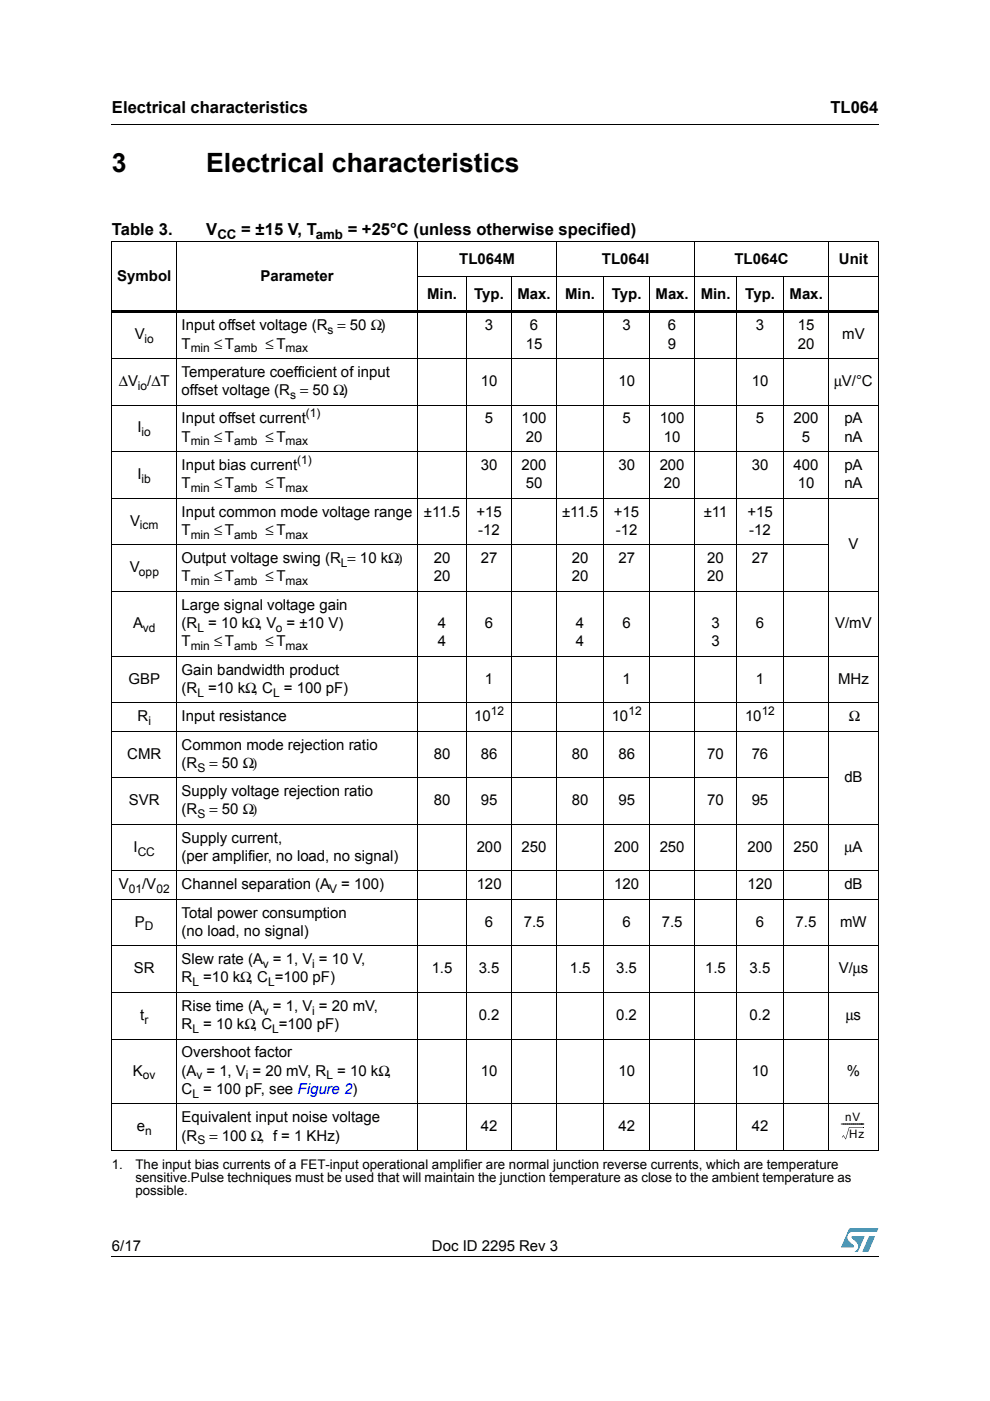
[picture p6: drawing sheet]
<svg xmlns="http://www.w3.org/2000/svg" width="210mm" height="297mm" viewBox="0 0 210 297" stroke-linecap="round" stroke-linejoin="round" font-family="sans-serif">
<defs><g id="words">
<g font-size="5.6">
<text x="23.7" y="36.4">3</text>
<text x="43.7" y="36.4">Electrical characteristics</text>
</g>
<g font-size="3.5">
<text x="23.7" y="23.9">Electrical characteristics</text>
<text x="176.1" y="23.9">TL064</text>
<text x="23.7" y="49.8">Table 3.</text>
<text x="43.7" y="49.8">V</text>
<text x="51.2" y="49.8">= ±15 V, T</text>
<text x="73.7" y="49.8">= +25°C (unless otherwise specified)</text>
</g>
<g font-size="3.2">
<text x="24.9" y="59.6">Symbol</text>
<text x="55.2" y="59.6">Parameter</text>
<text x="97.4" y="55.9">TL064M</text>
<text x="127.6" y="55.9">TL064I</text>
<text x="155.7" y="55.9">TL064C</text>
<text x="177.9" y="55.9">Unit</text>
<text x="90.6" y="63.3">Min.</text>
<text x="100.6" y="63.3">Typ.</text>
<text x="109.7" y="63.3">Max.</text>
<text x="119.8" y="63.3">Min.</text>
<text x="129.7" y="63.3">Typ.</text>
<text x="139" y="63.3">Max.</text>
<text x="148.6" y="63.3">Min.</text>
<text x="158" y="63.3">Typ.</text>
<text x="167.4" y="63.3">Max.</text>
<text x="28.6" y="71.9">V</text>
<text x="38.5" y="70">Input offset voltage (R = 50 Ω)</text>
<text x="102.8" y="70">3</text>
<text x="112.4" y="70">6</text>
<text x="132" y="70">3</text>
<text x="141.6" y="70">6</text>
<text x="160.3" y="70">3</text>
<text x="169.1" y="70">15</text>
<text x="178.6" y="71.9">mV</text>
<text x="38.5" y="73.9">T</text>
<text x="45.4" y="73.9">≤ T</text>
<text x="56.3" y="73.9">≤ T</text>
<text x="111.5" y="73.9">15</text>
<text x="141.6" y="73.9">9</text>
<text x="169.1" y="73.9">20</text>
<text x="25.2" y="81.8">ΔV /ΔT</text>
<text x="38.5" y="79.9">Temperature coefficient of input</text>
<text x="38.5" y="83.8">offset voltage (R = 50 Ω)</text>
<text x="101.9" y="81.8">10</text>
<text x="131.1" y="81.8">10</text>
<text x="159.4" y="81.8">10</text>
<text x="176.8" y="81.8">μV/°C</text>
<text x="38.5" y="89.8">Input offset current</text>
<text x="102.8" y="89.8">5</text>
<text x="110.6" y="89.8">100</text>
<text x="132" y="89.8">5</text>
<text x="139.9" y="89.8">100</text>
<text x="160.3" y="89.8">5</text>
<text x="168.3" y="89.8">200</text>
<text x="179" y="89.8">pA</text>
<text x="29.2" y="91.7">I</text>
<text x="38.5" y="93.6">T</text>
<text x="45.4" y="93.6">≤ T</text>
<text x="56.3" y="93.6">≤ T</text>
<text x="111.5" y="93.6">20</text>
<text x="140.8" y="93.6">10</text>
<text x="170" y="93.6">5</text>
<text x="179" y="93.6">nA</text>
<text x="29.2" y="101.6">I</text>
<text x="38.5" y="99.6">Input bias current</text>
<text x="101.9" y="99.6">30</text>
<text x="110.6" y="99.6">200</text>
<text x="131.1" y="99.6">30</text>
<text x="139.9" y="99.6">200</text>
<text x="159.4" y="99.6">30</text>
<text x="168.3" y="99.6">400</text>
<text x="179" y="99.6">pA</text>
<text x="38.5" y="103.5">T</text>
<text x="45.4" y="103.5">≤ T</text>
<text x="56.3" y="103.5">≤ T</text>
<text x="111.5" y="103.5">50</text>
<text x="140.8" y="103.5">20</text>
<text x="169.1" y="103.5">10</text>
<text x="179" y="103.5">nA</text>
<text x="27.6" y="111.5">V</text>
<text x="38.5" y="109.5">Input common mode voltage range</text>
<text x="38.5" y="113.4">T</text>
<text x="45.4" y="113.4">≤ T</text>
<text x="56.3" y="113.4">≤ T</text>
<text x="89.9" y="109.5">±11.5</text>
<text x="101" y="109.5">+15</text>
<text x="101.4" y="113.4">-12</text>
<text x="119.2" y="109.5">±11.5</text>
<text x="130.2" y="109.5">+15</text>
<text x="130.6" y="113.4">-12</text>
<text x="149.2" y="109.5">±11</text>
<text x="158.5" y="109.5">+15</text>
<text x="158.9" y="113.4">-12</text>
<text x="38.5" y="119.4">Output voltage swing (R = 10 kΩ)</text>
<text x="92" y="119.4">20</text>
<text x="101.9" y="119.4">27</text>
<text x="121.2" y="119.4">20</text>
<text x="131.1" y="119.4">27</text>
<text x="150" y="119.4">20</text>
<text x="159.4" y="119.4">27</text>
<text x="179.9" y="116.4">V</text>
<text x="27.5" y="121.3">V</text>
<text x="38.5" y="123.3">T</text>
<text x="45.4" y="123.3">≤ T</text>
<text x="56.3" y="123.3">≤ T</text>
<text x="92" y="123.3">20</text>
<text x="121.2" y="123.3">20</text>
<text x="150" y="123.3">20</text>
<text x="38.5" y="129.3">Large signal voltage gain</text>
<text x="28.2" y="133.2">A</text>
<text x="38.5" y="137">T</text>
<text x="38.5" y="133.2">(R</text>
<text x="44.2" y="133.2">= 10 kΩ, V = ±10 V)</text>
<text x="45.4" y="137">≤ T</text>
<text x="56.3" y="137">≤ T</text>
<text x="92.8" y="133.2">4</text>
<text x="92.8" y="137">4</text>
<text x="102.8" y="133.2">6</text>
<text x="122.1" y="133.2">4</text>
<text x="122.1" y="137">4</text>
<text x="132" y="133.2">6</text>
<text x="150.8" y="133.2">3</text>
<text x="150.8" y="137">3</text>
<text x="160.3" y="133.2">6</text>
<text x="177.1" y="133.2">V/mV</text>
<text x="38.5" y="143">Gain bandwidth product</text>
<text x="27.2" y="145">GBP</text>
<text x="38.5" y="146.9">(R</text>
<text x="44.2" y="146.9">=10 kΩ, C</text>
<text x="60.2" y="146.9">= 100 pF)</text>
<text x="102.8" y="145">1</text>
<text x="132" y="145">1</text>
<text x="160.3" y="145">1</text>
<text x="177.7" y="145">MHz</text>
<text x="29.2" y="152.9">R</text>
<text x="38.5" y="152.9">Input resistance</text>
<text x="100.5" y="152.9">10</text>
<text x="129.7" y="152.9">10</text>
<text x="158" y="152.9">10</text>
<text x="179.9" y="152.9">Ω</text>
<text x="27" y="160.8">CMR</text>
<text x="38.5" y="158.9">Common mode rejection ratio</text>
<text x="92" y="160.8">80</text>
<text x="101.9" y="160.8">86</text>
<text x="121.2" y="160.8">80</text>
<text x="131.1" y="160.8">86</text>
<text x="150" y="160.8">70</text>
<text x="159.4" y="160.8">76</text>
<text x="38.5" y="162.8">(R</text>
<text x="44.4" y="162.8">= 50 Ω)</text>
<text x="179" y="165.8">dB</text>
<text x="27.3" y="170.7">SVR</text>
<text x="38.5" y="168.8">Supply voltage rejection ratio</text>
<text x="38.5" y="172.7">(R</text>
<text x="44.4" y="172.7">= 50 Ω)</text>
<text x="92" y="170.7">80</text>
<text x="101.9" y="170.7">95</text>
<text x="121.2" y="170.7">80</text>
<text x="131.1" y="170.7">95</text>
<text x="150" y="170.7">70</text>
<text x="159.4" y="170.7">95</text>
<text x="38.5" y="178.7">Supply current,</text>
<text x="28.3" y="180.6">I</text>
<text x="38.5" y="182.5">(per amplifier, no load, no signal)</text>
<text x="101.1" y="180.6">200</text>
<text x="110.6" y="180.6">250</text>
<text x="130.2" y="180.6">200</text>
<text x="139.9" y="180.6">250</text>
<text x="158.5" y="180.6">200</text>
<text x="168.2" y="180.6">250</text>
<text x="179.1" y="180.6">μA</text>
<text x="25.2" y="188.6">V</text>
<text x="30.1" y="188.6">/V</text>
<text x="38.5" y="188.6">Channel separation (A</text>
<text x="72.4" y="188.6">= 100)</text>
<text x="101.1" y="188.6">120</text>
<text x="130.2" y="188.6">120</text>
<text x="158.5" y="188.6">120</text>
<text x="179" y="188.6">dB</text>
<text x="28.6" y="196.5">P</text>
<text x="38.5" y="194.5">Total power consumption</text>
<text x="102.8" y="196.5">6</text>
<text x="111" y="196.5">7.5</text>
<text x="132" y="196.5">6</text>
<text x="140.3" y="196.5">7.5</text>
<text x="160.3" y="196.5">6</text>
<text x="168.7" y="196.5">7.5</text>
<text x="178.1" y="196.5">mW</text>
<text x="38.5" y="198.4">(no load, no signal)</text>
<text x="28.4" y="206.4">SR</text>
<text x="38.5" y="208.3">R</text>
<text x="38.5" y="204.4">Slew rate (A = 1, V = 10 V,</text>
<text x="43.1" y="208.3">=10 kΩ, C =100 pF)</text>
<text x="91.5" y="206.4">1.5</text>
<text x="101.5" y="206.4">3.5</text>
<text x="120.8" y="206.4">1.5</text>
<text x="130.7" y="206.4">3.5</text>
<text x="149.5" y="206.4">1.5</text>
<text x="158.9" y="206.4">3.5</text>
<text x="177.8" y="206.4">V/μs</text>
<text x="38.5" y="214.3">Rise time (A = 1, V = 20 mV,</text>
<text x="29.7" y="216.2">t</text>
<text x="38.5" y="218.2">R</text>
<text x="43.1" y="218.2">= 10 kΩ, C =100 pF)</text>
<text x="101.5" y="216.2">0.2</text>
<text x="130.7" y="216.2">0.2</text>
<text x="158.9" y="216.2">0.2</text>
<text x="179.3" y="216.2">μs</text>
<text x="38.5" y="224.2">Overshoot factor</text>
<text x="28.2" y="228">K</text>
<text x="38.5" y="228">(A = 1, V = 20 mV, R</text>
<text x="38.5" y="231.9">C</text>
<text x="43.1" y="231.9">= 100 pF, see Figure 2)</text>
<text x="71.5" y="228">= 10 kΩ,</text>
<text x="101.9" y="228">10</text>
<text x="131.1" y="228">10</text>
<text x="159.4" y="228">10</text>
<text x="179.6" y="228">%</text>
<text x="29" y="239.9">e</text>
<text x="38.5" y="237.9">Equivalent input noise voltage</text>
<text x="101.9" y="239.9">42</text>
<text x="131.1" y="239.9">42</text>
<text x="159.4" y="239.9">42</text>
<text x="38.5" y="241.8">(R</text>
<text x="44.4" y="241.8">= 100 Ω, f = 1 KHz)</text>
<text x="23.7" y="265.1">6/17</text>
<text x="91.6" y="265.1">Doc ID 2295 Rev 3</text>
</g>
<g font-size="2.8">
<text x="46.1" y="50.7">CC</text>
<text x="67" y="50.7">amb</text>
<text x="23.7" y="247.8">1.</text>
<text x="28.7" y="247.8">The input bias currents of a FET-input operational amplifier are normal junction reverse currents, which are temperature</text>
<text x="28.7" y="250.6">sensitive.Pulse techniques must be used that will maintain the junction temperature as close to the ambient temperature as</text>
<text x="28.7" y="253.4">possible.</text>
</g>
<g font-size="2.5">
<text x="69.4" y="70.8">s</text>
<text x="30.6" y="72.7">io</text>
<text x="40.4" y="74.7">min</text>
<text x="49.6" y="74.7">amb</text>
<text x="60.6" y="74.7">max</text>
<text x="29.2" y="82.6">io</text>
<text x="61.5" y="84.6">s</text>
<text x="64.9" y="88.5">(1)</text>
<text x="30" y="92.5">io</text>
<text x="40.4" y="94.4">min</text>
<text x="49.6" y="94.4">amb</text>
<text x="60.6" y="94.4">max</text>
<text x="63" y="98.4">(1)</text>
<text x="30" y="102.4">ib</text>
<text x="40.4" y="104.3">min</text>
<text x="49.6" y="104.3">amb</text>
<text x="60.6" y="104.3">max</text>
<text x="29.7" y="112.2">icm</text>
<text x="40.4" y="114.2">min</text>
<text x="49.6" y="114.2">amb</text>
<text x="60.6" y="114.2">max</text>
<text x="29.5" y="122.1">opp</text>
<text x="40.4" y="124.1">min</text>
<text x="49.6" y="124.1">amb</text>
<text x="60.6" y="124.1">max</text>
<text x="72.3" y="120.2">L</text>
<text x="30.3" y="133.9">vd</text>
<text x="40.4" y="137.8">min</text>
<text x="41.8" y="133.9">L</text>
<text x="49.6" y="137.8">amb</text>
<text x="58.5" y="133.9">o</text>
<text x="60.6" y="137.8">max</text>
<text x="41.8" y="147.7">L</text>
<text x="57.9" y="147.7">L</text>
<text x="31.5" y="153.7">i</text>
<text x="104.1" y="151.6">12</text>
<text x="133.2" y="151.6">12</text>
<text x="161.5" y="151.6">12</text>
<text x="41.8" y="163.6">S</text>
<text x="41.8" y="173.5">S</text>
<text x="29.2" y="181.4">CC</text>
<text x="27.3" y="189.3">01</text>
<text x="33.1" y="189.3">02</text>
<text x="69.8" y="189.3">V</text>
<text x="30.7" y="197.3">D</text>
<text x="40.8" y="209.1">L</text>
<text x="55.7" y="205.2">v</text>
<text x="56.9" y="209.1">L</text>
<text x="66.2" y="205.2">i</text>
<text x="55.7" y="215.1">v</text>
<text x="66.2" y="215.1">i</text>
<text x="30.6" y="217">r</text>
<text x="40.8" y="219">L</text>
<text x="57.7" y="219">L</text>
<text x="30.3" y="228.9">ov</text>
<text x="40.8" y="232.7">L</text>
<text x="41.6" y="228.9">v</text>
<text x="52.1" y="228.9">i</text>
<text x="69.2" y="228.9">L</text>
<text x="178.3" y="238.9">-----------</text>
<text x="179.2" y="237.6">nV</text>
<text x="30.8" y="240.7">n</text>
<text x="41.8" y="242.6">S</text>
<text x="180" y="241.2">Hz</text>
</g>
</g></defs>
<g fill="#0099d8">
<path d="M184.3 262.1h1.2l-1.4 3.3h-1.3z"/>
<path d="M180.1 260.5h6.1l-.3 .7h-5.1a1.13 1.13 0 0 0-1.1 .7 1.13 1.13 0 0 0 .3 1.2l1 1v.3l-2.7 .1z"/>
<path d="M180.6 262.1h2.7l-1.4 3.3h-.7a1.18 1.18 0 0 0 .5-1.9l-1.1-1.1z"/>
</g>
<path d="M23.6 26.2l.1 .2zM23.6 65.9h162.7v.5h-162.7zM180 239h.1l-.7 2.5h-.1zM183 239v.1zM178.5 241.1l.1 .1zM178.8 240.7l-.2 .5zM179.3 241.5h.1zM178.8 240.7l.5 .8zM23.6 266.3l.1 .1z" fill="#000"/>
<g fill="none" stroke="#000" stroke-width=".21">
<path d="M23.7 26.3h162.6M23.6 51.3h162.7M23.7 51.4v24.5M37.4 51.2v24.9M88.4 58.7h97.9M88.5 51.2v192.8M98.9 58.6v185.4M108.5 58.6v185.4M118 51.2v192.8M128 58.6v185.4M137.8 58.6v185.4M147.3 51.2v192.8"/>
<path d="M156.2 58.6v185.4M166.1 58.6v185.4M175.7 51.2v192.8M186.2 51.4v192.4M23.7 76.1v9.7M37.5 75.9v10.1M186.3 76h-162.7M23.6 85.9h162.7M23.6 95.8h162.7M23.7 86v157.8M37.4 85.8v158.2M23.6 105.6h162.7"/>
<path d="M23.6 115.5h152.2M23.6 125.4h162.7M23.6 139.1h162.7M23.6 149h162.7M23.6 155h162.7M23.6 164.9h152.2M23.6 174.8h162.7M23.6 184.7h162.7M23.6 190.7h162.7M23.6 200.5h162.7M23.6 210.4h162.7M23.6 220.3h162.7"/>
<path d="M23.6 234.1h162.7M180 239h3M23.6 243.9h162.7M23.7 266.3h162.6"/>
</g>
<use href="#words"/>
</svg>
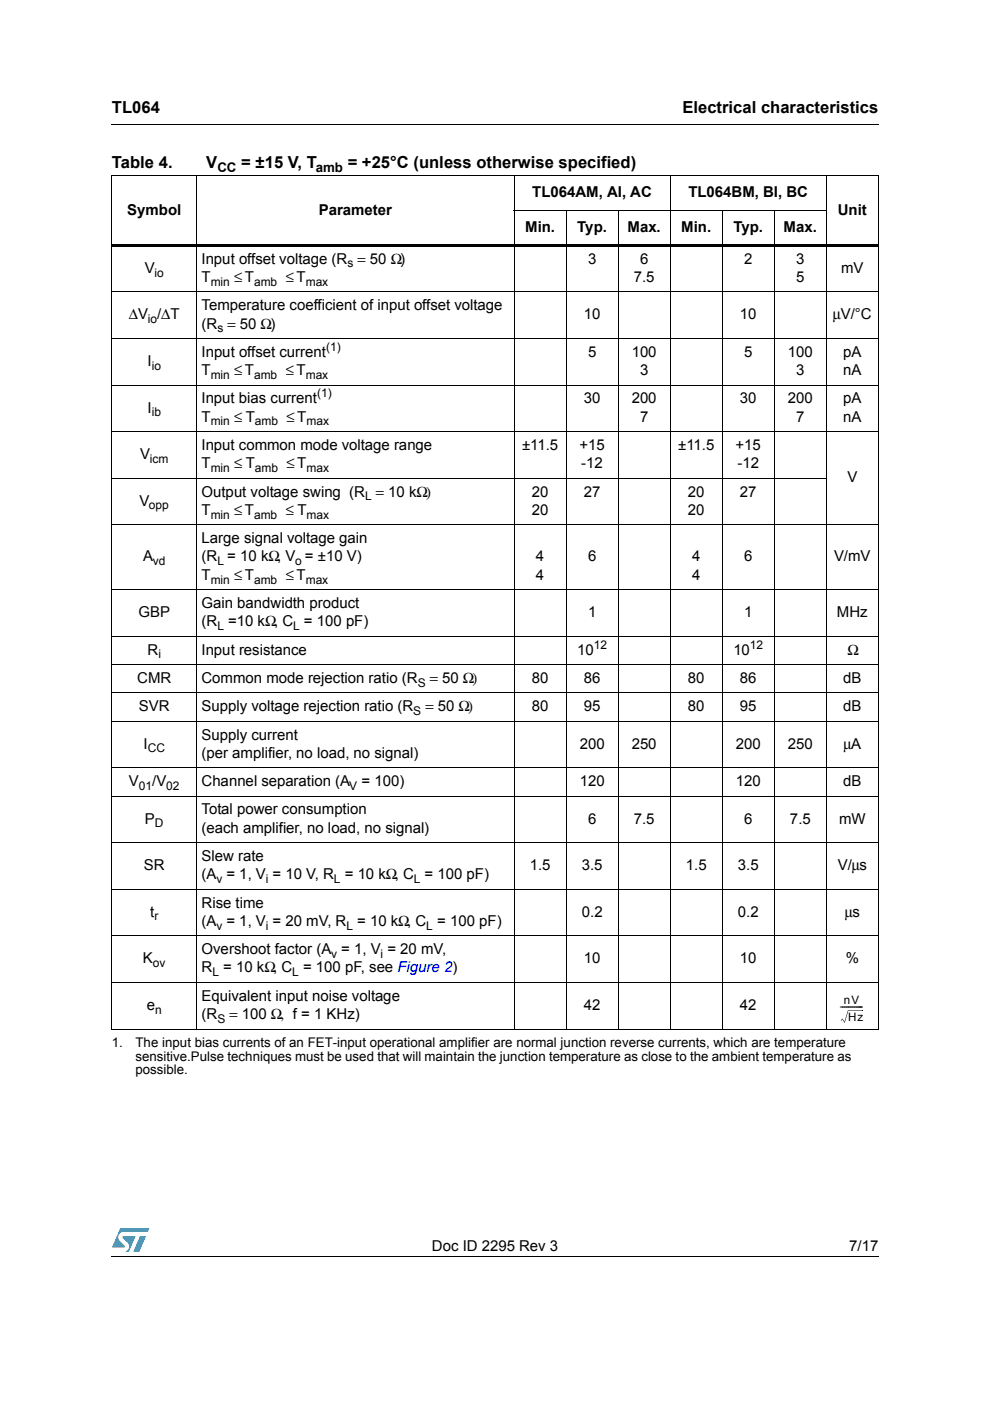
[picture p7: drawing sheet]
<svg xmlns="http://www.w3.org/2000/svg" width="210mm" height="297mm" viewBox="0 0 210 297" stroke-linecap="round" stroke-linejoin="round" font-family="sans-serif">
<defs><g id="words">
<g font-size="3.5">
<text x="23.7" y="23.9">TL064</text>
<text x="144.7" y="23.9">Electrical characteristics</text>
<text x="23.7" y="35.7">Table 4.</text>
<text x="43.7" y="35.7">V</text>
<text x="51.2" y="35.7">= ±15 V, T</text>
<text x="73.7" y="35.7">= +25°C (unless otherwise specified)</text>
</g>
<g font-size="3.2">
<text x="112.9" y="41.8">TL064AM, AI, AC</text>
<text x="146" y="41.8">TL064BM, BI, BC</text>
<text x="27" y="45.5">Symbol</text>
<text x="67.6" y="45.5">Parameter</text>
<text x="177.6" y="45.5">Unit</text>
<text x="111.4" y="49.2">Min.</text>
<text x="122.4" y="49.2">Typ.</text>
<text x="133.1" y="49.2">Max.</text>
<text x="144.5" y="49.2">Min.</text>
<text x="155.5" y="49.2">Typ.</text>
<text x="166.2" y="49.2">Max.</text>
<text x="30.7" y="57.8">V</text>
<text x="42.7" y="55.9">Input offset voltage (R = 50 Ω)</text>
<text x="42.7" y="59.8">T</text>
<text x="49.7" y="59.8">≤ T</text>
<text x="60.6" y="59.8">≤ T</text>
<text x="124.7" y="55.9">3</text>
<text x="134.4" y="59.8">7.5</text>
<text x="135.7" y="55.9">6</text>
<text x="157.8" y="55.9">2</text>
<text x="168.8" y="55.9">3</text>
<text x="168.8" y="59.8">5</text>
<text x="178.4" y="57.8">mV</text>
<text x="42.7" y="65.8">Temperature coefficient of input offset voltage</text>
<text x="27.3" y="67.7">ΔV /ΔT</text>
<text x="42.7" y="69.7">(R = 50 Ω)</text>
<text x="123.8" y="67.7">10</text>
<text x="156.9" y="67.7">10</text>
<text x="176.6" y="67.7">μV/°C</text>
<text x="31.3" y="77.6">I</text>
<text x="42.7" y="75.6">Input offset current</text>
<text x="124.7" y="75.6">5</text>
<text x="133.9" y="75.6">100</text>
<text x="157.8" y="75.6">5</text>
<text x="167" y="75.6">100</text>
<text x="178.8" y="75.6">pA</text>
<text x="42.7" y="79.5">T</text>
<text x="49.7" y="79.5">≤ T</text>
<text x="60.6" y="79.5">≤ T</text>
<text x="135.7" y="79.5">3</text>
<text x="168.8" y="79.5">3</text>
<text x="178.8" y="79.5">nA</text>
<text x="31.3" y="87.5">I</text>
<text x="42.7" y="85.5">Input bias current</text>
<text x="42.7" y="89.4">T</text>
<text x="49.7" y="89.4">≤ T</text>
<text x="60.7" y="89.4">≤ T</text>
<text x="123.8" y="85.5">30</text>
<text x="133.9" y="85.5">200</text>
<text x="135.7" y="89.4">7</text>
<text x="156.9" y="85.5">30</text>
<text x="167" y="85.5">200</text>
<text x="168.8" y="89.4">7</text>
<text x="178.8" y="85.5">pA</text>
<text x="178.8" y="89.4">nA</text>
<text x="42.7" y="95.4">Input common mode voltage range</text>
<text x="110.7" y="95.4">±11.5</text>
<text x="122.9" y="95.4">+15</text>
<text x="143.8" y="95.4">±11.5</text>
<text x="155.9" y="95.4">+15</text>
<text x="29.7" y="97.3">V</text>
<text x="42.7" y="99.3">T</text>
<text x="49.7" y="99.3">≤ T</text>
<text x="60.7" y="99.3">≤ T</text>
<text x="123.3" y="99.3">-12</text>
<text x="156.4" y="99.3">-12</text>
<text x="29.6" y="107.2">V</text>
<text x="42.7" y="105.3">Output voltage swing (R</text>
<text x="79.7" y="105.3">= 10 kΩ)</text>
<text x="112.8" y="105.3">20</text>
<text x="123.8" y="105.3">27</text>
<text x="145.9" y="105.3">20</text>
<text x="156.9" y="105.3">27</text>
<text x="179.7" y="102.3">V</text>
<text x="42.7" y="109.2">T</text>
<text x="49.7" y="109.2">≤ T</text>
<text x="60.6" y="109.2">≤ T</text>
<text x="112.8" y="109.2">20</text>
<text x="145.9" y="109.2">20</text>
<text x="30.3" y="119">A</text>
<text x="42.7" y="115.2">Large signal voltage gain</text>
<text x="42.7" y="119">(R = 10 kΩ, V = ±10 V)</text>
<text x="113.6" y="119">4</text>
<text x="124.7" y="119">6</text>
<text x="146.7" y="119">4</text>
<text x="157.8" y="119">6</text>
<text x="176.8" y="119">V/mV</text>
<text x="42.7" y="122.9">T</text>
<text x="49.7" y="122.9">≤ T</text>
<text x="60.6" y="122.9">≤ T</text>
<text x="113.6" y="122.9">4</text>
<text x="146.7" y="122.9">4</text>
<text x="29.4" y="130.9">GBP</text>
<text x="42.7" y="128.9">Gain bandwidth product</text>
<text x="124.7" y="130.9">1</text>
<text x="157.8" y="130.9">1</text>
<text x="177.5" y="130.9">MHz</text>
<text x="42.7" y="132.8">(R</text>
<text x="48.4" y="132.8">=10 kΩ, C</text>
<text x="64.5" y="132.8">= 100 pF)</text>
<text x="31.3" y="138.8">R</text>
<text x="42.7" y="138.8">Input resistance</text>
<text x="122.4" y="138.8">10</text>
<text x="155.5" y="138.8">10</text>
<text x="179.7" y="138.8">Ω</text>
<text x="29.1" y="144.8">CMR</text>
<text x="42.7" y="144.8">Common mode rejection ratio (R</text>
<text x="91.1" y="144.8">= 50 Ω)</text>
<text x="112.8" y="144.8">80</text>
<text x="123.8" y="144.8">86</text>
<text x="145.9" y="144.8">80</text>
<text x="156.9" y="144.8">86</text>
<text x="178.8" y="144.8">dB</text>
<text x="29.4" y="150.8">SVR</text>
<text x="42.7" y="150.8">Supply voltage rejection ratio (R</text>
<text x="90.2" y="150.8">= 50 Ω)</text>
<text x="112.8" y="150.8">80</text>
<text x="123.8" y="150.8">95</text>
<text x="145.9" y="150.8">80</text>
<text x="156.9" y="150.8">95</text>
<text x="178.8" y="150.8">dB</text>
<text x="30.4" y="158.7">I</text>
<text x="42.7" y="156.8">Supply current</text>
<text x="42.7" y="160.7">(per amplifier, no load, no signal)</text>
<text x="122.9" y="158.7">200</text>
<text x="133.9" y="158.7">250</text>
<text x="156" y="158.7">200</text>
<text x="167" y="158.7">250</text>
<text x="178.8" y="158.7">μA</text>
<text x="27.3" y="166.7">V</text>
<text x="32.3" y="166.7">/V</text>
<text x="42.7" y="166.7">Channel separation (A</text>
<text x="76.6" y="166.7">= 100)</text>
<text x="122.9" y="166.7">120</text>
<text x="156" y="166.7">120</text>
<text x="178.8" y="166.7">dB</text>
<text x="42.7" y="172.7">Total power consumption</text>
<text x="30.7" y="174.6">P</text>
<text x="42.7" y="176.6">(each amplifier, no load, no signal)</text>
<text x="124.7" y="174.6">6</text>
<text x="134.4" y="174.6">7.5</text>
<text x="157.8" y="174.6">6</text>
<text x="167.5" y="174.6">7.5</text>
<text x="177.9" y="174.6">mW</text>
<text x="30.5" y="184.5">SR</text>
<text x="42.7" y="182.5">Slew rate</text>
<text x="112.3" y="184.5">1.5</text>
<text x="123.4" y="184.5">3.5</text>
<text x="145.4" y="184.5">1.5</text>
<text x="156.4" y="184.5">3.5</text>
<text x="177.6" y="184.5">V/μs</text>
<text x="42.7" y="186.4">(A = 1, V = 10 V, R</text>
<text x="73.1" y="186.4">= 10 kΩ, C</text>
<text x="90" y="186.4">= 100 pF)</text>
<text x="31.9" y="194.4">t</text>
<text x="42.7" y="192.4">Rise time</text>
<text x="42.7" y="196.3">(A = 1, V = 20 mV, R</text>
<text x="75.8" y="196.3">= 10 kΩ, C</text>
<text x="92.7" y="196.3">= 100 pF)</text>
<text x="123.4" y="194.4">0.2</text>
<text x="156.5" y="194.4">0.2</text>
<text x="179.1" y="194.4">μs</text>
<text x="42.7" y="202.3">Overshoot factor (A = 1, V = 20 mV,</text>
<text x="30.3" y="204.2">K</text>
<text x="42.7" y="206.2">R</text>
<text x="47.3" y="206.2">= 10 kΩ, C</text>
<text x="64.3" y="206.2">= 100 pF, see Figure 2)</text>
<text x="123.8" y="204.2">10</text>
<text x="156.9" y="204.2">10</text>
<text x="179.3" y="204.2">%</text>
<text x="31.1" y="214.1">e</text>
<text x="42.7" y="212.2">Equivalent input noise voltage</text>
<text x="123.8" y="214.1">42</text>
<text x="156.9" y="214.1">42</text>
<text x="42.7" y="216.1">(R</text>
<text x="48.7" y="216.1">= 100 Ω, f = 1 KHz)</text>
<text x="91.6" y="265.1">Doc ID 2295 Rev 3</text>
<text x="180.1" y="265.1">7/17</text>
</g>
<g font-size="2.8">
<text x="46.1" y="36.6">CC</text>
<text x="67" y="36.6">amb</text>
<text x="23.7" y="222.1">1.</text>
<text x="28.7" y="222.1">The input bias currents of an FET-input operational amplifier are normal junction reverse currents, which are temperature</text>
<text x="28.7" y="224.9">sensitive.Pulse techniques must be used that will maintain the junction temperature as close to the ambient temperature as</text>
<text x="28.7" y="227.7">possible.</text>
</g>
<g font-size="2.5">
<text x="32.8" y="58.6">io</text>
<text x="73.7" y="56.7">s</text>
<text x="44.7" y="60.6">min</text>
<text x="53.9" y="60.6">amb</text>
<text x="64.8" y="60.6">max</text>
<text x="31.3" y="68.5">io</text>
<text x="46.1" y="70.4">s</text>
<text x="69.1" y="74.4">(1)</text>
<text x="32.2" y="78.4">io</text>
<text x="44.7" y="80.3">min</text>
<text x="53.9" y="80.3">amb</text>
<text x="64.8" y="80.3">max</text>
<text x="32.2" y="88.3">ib</text>
<text x="67.2" y="84.3">(1)</text>
<text x="44.7" y="90.2">min</text>
<text x="54.1" y="90.2">amb</text>
<text x="65" y="90.2">max</text>
<text x="31.8" y="98.1">icm</text>
<text x="44.7" y="100.1">min</text>
<text x="54.1" y="100.1">amb</text>
<text x="65" y="100.1">max</text>
<text x="77.4" y="106.1">L</text>
<text x="31.6" y="108">opp</text>
<text x="44.7" y="110">min</text>
<text x="53.9" y="110">amb</text>
<text x="65" y="110">max</text>
<text x="32.4" y="119.8">vd</text>
<text x="46.1" y="119.8">L</text>
<text x="62.5" y="119.8">o</text>
<text x="44.7" y="123.7">min</text>
<text x="53.9" y="123.7">amb</text>
<text x="64.8" y="123.7">max</text>
<text x="46.1" y="133.6">L</text>
<text x="62.1" y="133.6">L</text>
<text x="125.9" y="137.5">12</text>
<text x="159" y="137.5">12</text>
<text x="33.6" y="139.6">i</text>
<text x="88.6" y="145.6">S</text>
<text x="87.6" y="151.6">S</text>
<text x="31.3" y="159.5">CC</text>
<text x="29.4" y="167.5">01</text>
<text x="35.3" y="167.5">02</text>
<text x="74.1" y="167.5">V</text>
<text x="32.9" y="175.4">D</text>
<text x="45.9" y="187.2">v</text>
<text x="56.3" y="187.2">i</text>
<text x="70.8" y="187.2">L</text>
<text x="87.8" y="187.2">L</text>
<text x="32.7" y="195.2">r</text>
<text x="45.9" y="197.1">v</text>
<text x="56.3" y="197.1">i</text>
<text x="73.4" y="197.1">L</text>
<text x="90.4" y="197.1">L</text>
<text x="70.2" y="203.1">v</text>
<text x="80.7" y="203.1">i</text>
<text x="32.4" y="205">ov</text>
<text x="45" y="207">L</text>
<text x="62" y="207">L</text>
<text x="32.9" y="214.9">n</text>
<text x="178.1" y="214.1">-----------</text>
<text x="178.9" y="212.8">nV</text>
<text x="46.1" y="216.9">S</text>
<text x="179.8" y="216.5">Hz</text>
</g>
</g></defs>
<g fill="#0099d8">
<path d="M29.7 262.1h1.3l-1.5 3.3h-1.2z"/>
<path d="M25.5 260.5h6.2l-.4 .7h-5.1a1.13 1.13 0 0 0-1.1 .7 1.13 1.13 0 0 0 .3 1.2l1.1 1-.1 .3-2.7 .1z"/>
<path d="M26 262.1h2.8l-1.5 3.3h-.7a1.18 1.18 0 0 0 .5-1.9l-1.1-1.1z"/>
</g>
<path d="M23.6 26.2l.1 .2zM23.6 51.8h162.7v.5h-162.7zM178.3 216.3l.1 .2zM178.5 216l-.1 .4zM179 216.8l.1-.1zM178.6 215.9l.4 .9zM179 216.7l.1 .1zM179.8 214.2l.1 .1-.8 2.4h-.1zM182.8 214.2v.1zM23.6 266.3l.1 .1z" fill="#000"/>
<g fill="none" stroke="#000" stroke-width=".21">
<path d="M23.6 37.2h162.7M23.7 37.3v24.5M23.7 26.3h162.6M41.7 37.1v181.2M109 37.1v181.2M142.1 37.1v181.2M175.2 37.1v181.2M186.2 37.3v180.8M108.9 44.6h66.4M120 44.5v173.8M131.1 44.5v173.8M153.1 44.5v173.8"/>
<path d="M164.2 44.5v173.8M23.6 61.9h162.7M23.6 71.8h162.7M23.7 71.9v146.2M23.7 62v9.7M23.6 81.6h162.7M23.6 91.5h162.7M23.6 101.4h151.7M23.6 111.3h162.7M23.6 125.1h162.7M23.6 134.9h162.7M23.6 140.9h162.7"/>
<path d="M23.6 146.9h162.7M23.6 152.9h162.7M23.6 162.8h162.7M23.6 168.8h162.7M23.6 178.7h162.7M23.6 188.6h162.7M23.6 198.4h162.7M23.6 208.3h162.7M23.6 218.2h162.7M179.8 214.3h3M23.7 266.3h162.6"/>
</g>
<use href="#words"/>
</svg>
